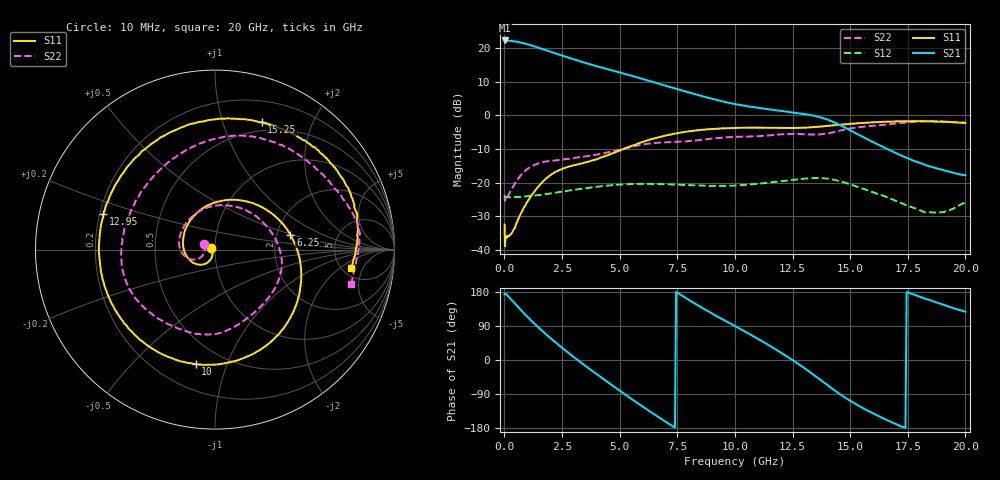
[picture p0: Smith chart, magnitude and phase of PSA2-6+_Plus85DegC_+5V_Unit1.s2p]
!Keysight Technologies,N5242A,MY47200155,A.10.49.08
!Date: Thursday, October 19, 2023 15:43:07
!Correction: S11(Full 2 Port(1,2))
!S21(Full 2 Port(1,2))
!S12(Full 2 Port(1,2))
!S22(Full 2 Port(1,2))
!S2P File: Measurements: S11, S21, S12, S22:
# Hz S  dB  R 50
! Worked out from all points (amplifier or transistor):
!   408 points, 10 MHz to 20 GHz, reference 50 ohm
!   highest |S21| = 22.2 dB at 20 MHz (marker M1)
!   |S21| within 3 dB of that: start of sweep to 1.845 GHz
!   unconditionally stable (mu >= 1): start of sweep to end of sweep
!   at 3.05 GHz: K = 1.10, MAG = 17.4 dB, |S12| = -22.2 dB
!   at 9.85 GHz: K = 1.57, MAG = 7.8 dB, |S12| = -21.0 dB
!   at 20 GHz: K = 12.09, MAG = -9.8 dB, |S12| = -25.9 dB
!   S11 on the Smith chart (normalised r, x): 10 MHz: 0.96, +0.02; 6.25 GHz: 2.38, +0.49; 10 GHz: 0.36, -0.78; 12.95 GHz: 0.22, +0.15; 15.25 GHz: 0.41, +1.35; 20 GHz: 6.06, -2.97
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1e7  -32.52 157.4  22.21 173.2  -24.28 -4.9  -23.67 153.7
2e7  -37.30 148.5  22.22 175.6  -24.17 -0.1  -25.09 162.2
3.5e8  -34.66 -137.2  22.03 155.8  -24.34 -5.8  -21.55 -152.3
7e8  -29.38 -116.1  21.60 132.8  -24.24 -11.0  -17.92 -154.1
9.5e8  -26.26 -113.7  21.18 117.1  -24.10 -14.9  -16.23 -160.6
1.25e9  -23.19 -116.4  20.57 99.0  -23.94 -19.6  -14.95 -171.0
1.75e9  -19.20 -130.5  19.44 70.9  -23.50 -28.4  -13.81 169.7
2.25e9  -16.75 -151.6  18.30 44.8  -22.98 -38.2  -13.40 147.5
2.75e9  -15.41 -175.7  17.18 20.1  -22.47 -49.0  -13.00 124.0
3.35e9  -14.34 154.3  15.88 -8.0  -21.87 -63.1  -12.40 97.2
4e9  -13.07 121.1  14.58 -37.1  -21.29 -79.5  -11.74 70.5
4.65e9  -11.43 86.5  13.36 -65.6  -20.80 -97.0  -10.80 44.2
6.25e9  -7.37 11.3  10.26 -133.3  -20.41 -141.6  -8.45 -10.3
6.7e9  -6.52 -5.5  9.36 -151.3  -20.47 -153.9  -8.16 -22.3
8.3e9  -4.54 -55.2  6.20 147.7  -20.84 165.1  -7.51 -63.8
1e10  -3.78 -99.7  3.32 89.7  -20.88 126.9  -6.44 -96.5
1.005e10  -3.77 -100.9  3.26 88.0  -20.88 125.8  -6.44 -97.6
1.295e10  -3.71 162.2  0.43 -18.4  -18.90 47.8  -5.64 -178.4
1.335e10  -3.58 144.3  -0.04 -36.0  -18.70 33.6  -5.79 163.6
1.525e10  -2.44 69.9  -5.37 -116.6  -21.12 -35.2  -3.67 75.2
1.67e10  -1.91 38.8  -10.31 -161.4  -24.66 -73.1  -2.69 33.4
2e10  -2.31 -7.6  -17.86 127.5  -25.90 -98.9  -2.16 -14.1
